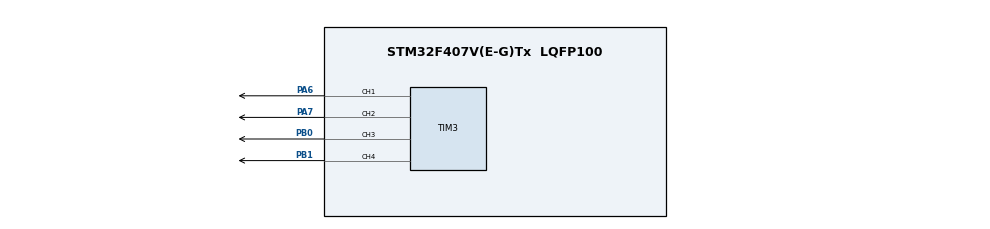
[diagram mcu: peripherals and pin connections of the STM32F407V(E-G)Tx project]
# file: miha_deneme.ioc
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Mcu.Family=STM32F4
Mcu.Name=STM32F407V(E-G)Tx
Mcu.Package=LQFP100
NVIC.PriorityGroup=NVIC_PRIORITYGROUP_4
PA6.Signal=S_TIM3_CH1
PA7.Signal=S_TIM3_CH2
PB0.Signal=S_TIM3_CH3
PB1.Signal=S_TIM3_CH4
ProjectManager.HeapSize=0x200
ProjectManager.StackSize=0x400
ProjectManager.TargetToolchain=STM32CubeIDE
RCC.48MHZClocksFreq_Value=36000000
RCC.AHBFreq_Value=72000000
RCC.APB1CLKDivider=RCC_HCLK_DIV2
RCC.APB1Freq_Value=36000000
RCC.APB1TimFreq_Value=72000000
RCC.APB2Freq_Value=72000000
RCC.APB2TimFreq_Value=72000000
RCC.CortexFreq_Value=72000000
RCC.HCLKFreq_Value=72000000
RCC.HSE_VALUE=25000000
RCC.HSI_VALUE=16000000
RCC.LSE_VALUE=32768
RCC.PLLM=8
RCC.PLLN=72
RCC.SYSCLKFreq_VALUE=72000000
RCC.SYSCLKSource=RCC_SYSCLKSOURCE_PLLCLK
RCC.VCOOutputFreq_Value=144000000
SH.S_TIM3_CH1.0=TIM3_CH1,PWM Generation1 CH1
SH.S_TIM3_CH2.0=TIM3_CH2,PWM Generation2 CH2
SH.S_TIM3_CH3.0=TIM3_CH3,PWM Generation3 CH3
SH.S_TIM3_CH4.0=TIM3_CH4,PWM Generation4 CH4
TIM3.Channel-PWM\ Generation1\ CH1=TIM_CHANNEL_1
TIM3.Channel-PWM\ Generation2\ CH2=TIM_CHANNEL_2
TIM3.Channel-PWM\ Generation3\ CH3=TIM_CHANNEL_3
TIM3.Channel-PWM\ Generation4\ CH4=TIM_CHANNEL_4
board=custom

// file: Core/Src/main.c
/* USER CODE BEGIN Header */
/**
  ******************************************************************************
  * @file           : main.c
  * @brief          : Main program body
  ******************************************************************************
  * @attention
  *
  * <h2><center>&copy; Copyright (c) 2021 STMicroelectronics.
  * All rights reserved.</center></h2>
  *
  * This software component is licensed by ST under BSD 3-Clause license,
  * the "License"; You may not use this file except in compliance with the
  * License. You may obtain a copy of the License at:
  *                        opensource.org/licenses/BSD-3-Clause
  *
  ******************************************************************************
  */
/* USER CODE END Header */
#include "main.h"

TIM_HandleTypeDef htim3;

void SystemClock_Config(void);
static void MX_GPIO_Init(void);
static void MX_TIM3_Init(void);

int main(void)
{

  /* MCU Configuration--------------------------------------------------------*/

  /* Reset of all peripherals, Initializes the Flash interface and the Systick. */
  HAL_Init();

  /* Configure the system clock */
  SystemClock_Config();

  /* Initialize all configured peripherals */
  MX_GPIO_Init();
  MX_TIM3_Init();

  /* Infinite loop */
  while (1)
  {

  }
}

void SystemClock_Config(void)
{
  RCC_OscInitTypeDef RCC_OscInitStruct = {0};
  RCC_ClkInitTypeDef RCC_ClkInitStruct = {0};

  /** Configure the main internal regulator output voltage
  */
  __HAL_RCC_PWR_CLK_ENABLE();
  __HAL_PWR_VOLTAGESCALING_CONFIG(PWR_REGULATOR_VOLTAGE_SCALE1);
  /** Initializes the RCC Oscillators according to the specified parameters
  * in the RCC_OscInitTypeDef structure.
  */
  RCC_OscInitStruct.OscillatorType = RCC_OSCILLATORTYPE_HSI;
  RCC_OscInitStruct.HSIState = RCC_HSI_ON;
  RCC_OscInitStruct.HSICalibrationValue = RCC_HSICALIBRATION_DEFAULT;
  RCC_OscInitStruct.PLL.PLLState = RCC_PLL_NONE;
  if (HAL_RCC_OscConfig(&RCC_OscInitStruct) != HAL_OK)
  {
    Error_Handler();
  }
  /** Initializes the CPU, AHB and APB buses clocks
  */
  RCC_ClkInitStruct.ClockType = RCC_CLOCKTYPE_HCLK|RCC_CLOCKTYPE_SYSCLK
                              |RCC_CLOCKTYPE_PCLK1|RCC_CLOCKTYPE_PCLK2;
  RCC_ClkInitStruct.SYSCLKSource = RCC_SYSCLKSOURCE_HSI;
  RCC_ClkInitStruct.AHBCLKDivider = RCC_SYSCLK_DIV1;
  RCC_ClkInitStruct.APB1CLKDivider = RCC_HCLK_DIV1;
  RCC_ClkInitStruct.APB2CLKDivider = RCC_HCLK_DIV1;

  if (HAL_RCC_ClockConfig(&RCC_ClkInitStruct, FLASH_LATENCY_0) != HAL_OK)
  {
    Error_Handler();
  }
}

static void MX_TIM3_Init(void)
{

  TIM_MasterConfigTypeDef sMasterConfig = {0};
  TIM_OC_InitTypeDef sConfigOC = {0};

  htim3.Instance = TIM3;
  htim3.Init.Prescaler = 0;
  htim3.Init.CounterMode = TIM_COUNTERMODE_UP;
  htim3.Init.Period = 65535;
  htim3.Init.ClockDivision = TIM_CLOCKDIVISION_DIV1;
  htim3.Init.AutoReloadPreload = TIM_AUTORELOAD_PRELOAD_DISABLE;
  if (HAL_TIM_PWM_Init(&htim3) != HAL_OK)
  {
    Error_Handler();
  }
  sMasterConfig.MasterOutputTrigger = TIM_TRGO_RESET;
  sMasterConfig.MasterSlaveMode = TIM_MASTERSLAVEMODE_DISABLE;
  if (HAL_TIMEx_MasterConfigSynchronization(&htim3, &sMasterConfig) != HAL_OK)
  {
    Error_Handler();
  }
  sConfigOC.OCMode = TIM_OCMODE_PWM1;
  sConfigOC.Pulse = 0;
  sConfigOC.OCPolarity = TIM_OCPOLARITY_HIGH;
  sConfigOC.OCFastMode = TIM_OCFAST_DISABLE;
  if (HAL_TIM_PWM_ConfigChannel(&htim3, &sConfigOC, TIM_CHANNEL_1) != HAL_OK)
  {
    Error_Handler();
  }
  if (HAL_TIM_PWM_ConfigChannel(&htim3, &sConfigOC, TIM_CHANNEL_2) != HAL_OK)
  {
    Error_Handler();
  }
  if (HAL_TIM_PWM_ConfigChannel(&htim3, &sConfigOC, TIM_CHANNEL_3) != HAL_OK)
  {
    Error_Handler();
  }
  if (HAL_TIM_PWM_ConfigChannel(&htim3, &sConfigOC, TIM_CHANNEL_4) != HAL_OK)
  {
    Error_Handler();
  }
  HAL_TIM_MspPostInit(&htim3);

}

static void MX_GPIO_Init(void)
{

  /* GPIO Ports Clock Enable */
  __HAL_RCC_GPIOA_CLK_ENABLE();
  __HAL_RCC_GPIOB_CLK_ENABLE();

}

void Error_Handler(void)
{
  __disable_irq();
  while (1)
  {
  }
}

/************************ (C) COPYRIGHT STMicroelectronics *****END OF FILE****/
